VERSION 5.8 ;
BUSBITCHARS "[]" ;
DIVIDERCHAR "/" ;

UNITS
  DATABASE MICRONS 2000 ;
END UNITS

MANUFACTURINGGRID 0.005 ;

SITE core7T
  CLASS CORE ;
  SYMMETRY X Y ;
  SIZE 0.140 BY 0.700 ;
END core7T

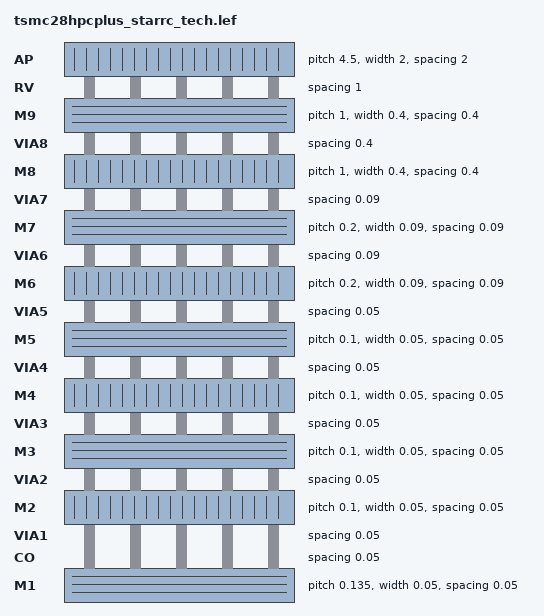
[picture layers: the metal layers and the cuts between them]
LAYER M1
  TYPE ROUTING ;
  DIRECTION HORIZONTAL ;
  PITCH 0.135 ;
  WIDTH 0.050 ;
  SPACING 0.050 ;
END M1

LAYER CO
  TYPE CUT ;
  SPACING 0.050 ;
END CO

LAYER VIA1
  TYPE CUT ;
  SPACING 0.050 ;
END VIA1

LAYER M2
  TYPE ROUTING ;
  DIRECTION VERTICAL ;
  PITCH 0.100 ;
  WIDTH 0.050 ;
  SPACING 0.050 ;
END M2

LAYER VIA2
  TYPE CUT ;
  SPACING 0.050 ;
END VIA2

LAYER M3
  TYPE ROUTING ;
  DIRECTION HORIZONTAL ;
  PITCH 0.100 ;
  WIDTH 0.050 ;
  SPACING 0.050 ;
END M3

LAYER VIA3
  TYPE CUT ;
  SPACING 0.050 ;
END VIA3

LAYER M4
  TYPE ROUTING ;
  DIRECTION VERTICAL ;
  PITCH 0.100 ;
  WIDTH 0.050 ;
  SPACING 0.050 ;
END M4

LAYER VIA4
  TYPE CUT ;
  SPACING 0.050 ;
END VIA4

LAYER M5
  TYPE ROUTING ;
  DIRECTION HORIZONTAL ;
  PITCH 0.100 ;
  WIDTH 0.050 ;
  SPACING 0.050 ;
END M5

LAYER VIA5
  TYPE CUT ;
  SPACING 0.050 ;
END VIA5

LAYER M6
  TYPE ROUTING ;
  DIRECTION VERTICAL ;
  PITCH 0.200 ;
  WIDTH 0.090 ;
  SPACING 0.090 ;
END M6

LAYER VIA6
  TYPE CUT ;
  SPACING 0.090 ;
END VIA6

LAYER M7
  TYPE ROUTING ;
  DIRECTION HORIZONTAL ;
  PITCH 0.200 ;
  WIDTH 0.090 ;
  SPACING 0.090 ;
END M7

LAYER VIA7
  TYPE CUT ;
  SPACING 0.090 ;
END VIA7

LAYER M8
  TYPE ROUTING ;
  DIRECTION VERTICAL ;
  PITCH 1.000 ;
  WIDTH 0.400 ;
  SPACING 0.400 ;
END M8

LAYER VIA8
  TYPE CUT ;
  SPACING 0.400 ;
END VIA8

LAYER M9
  TYPE ROUTING ;
  DIRECTION HORIZONTAL ;
  PITCH 1.000 ;
  WIDTH 0.400 ;
  SPACING 0.400 ;
END M9

LAYER RV
  TYPE CUT ;
  SPACING 1.000 ;
END RV

LAYER AP
  TYPE ROUTING ;
  DIRECTION VERTICAL ;
  PITCH 4.500 ;
  WIDTH 2.000 ;
  SPACING 2.000 ;
END AP

VIA VIA12_1cut DEFAULT
  LAYER M1 ;
    RECT -0.025 -0.055 0.025 0.055 ;
  LAYER VIA1 ;
    RECT -0.025 -0.025 0.025 0.025 ;
  LAYER M2 ;
    RECT -0.055 -0.025 0.055 0.025 ;
END VIA12_1cut

VIA VIA12_square
  LAYER M1 ;
    RECT -0.025 -0.055 0.025 0.055 ;
  LAYER VIA1 ;
    RECT -0.025 -0.025 0.025 0.025 ;
  LAYER M2 ;
    RECT -0.055 -0.025 0.055 0.025 ;
END VIA12_square

VIA VIA12_slot
  LAYER M1 ;
    RECT -0.075 -0.055 0.075 0.055 ;
  LAYER VIA1 ;
    RECT -0.065 -0.025 0.065 0.025 ;
  LAYER M2 ;
    RECT -0.105 -0.025 0.105 0.025 ;
END VIA12_slot

VIA VIA12_1cut_V
  LAYER M1 ;
    RECT -0.025 -0.055 0.025 0.055 ;
  LAYER VIA1 ;
    RECT -0.025 -0.025 0.025 0.025 ;
  LAYER M2 ;
    RECT -0.025 -0.055 0.025 0.055 ;
END VIA12_1cut_V

VIA VIA12_1cut_AS
  LAYER M1 ;
    RECT -0.045 -0.045 0.045 0.045 ;
  LAYER VIA1 ;
    RECT -0.025 -0.025 0.025 0.025 ;
  LAYER M2 ;
    RECT -0.045 -0.045 0.045 0.045 ;
END VIA12_1cut_AS

VIA VIA12_1cut_EN1415
  LAYER M1 ;
    RECT -0.035 -0.05 0.035 0.05 ;
  LAYER VIA1 ;
    RECT -0.025 -0.025 0.025 0.025 ;
  LAYER M2 ;
    RECT -0.05 -0.035 0.05 0.035 ;
END VIA12_1cut_EN1415

VIA VIA12_LONG_H
  LAYER M1 ;
    RECT -0.075 -0.055 0.075 0.055 ;
  LAYER VIA1 ;
    RECT -0.065 -0.025 0.065 0.025 ;
  LAYER M2 ;
    RECT -0.105 -0.025 0.105 0.025 ;
END VIA12_LONG_H

VIA VIA12_LONG_HH
  LAYER M1 ;
    RECT -0.105 -0.025 0.105 0.025 ;
  LAYER VIA1 ;
    RECT -0.065 -0.025 0.065 0.025 ;
  LAYER M2 ;
    RECT -0.105 -0.025 0.105 0.025 ;
END VIA12_LONG_HH

VIA VIA12_LONG_V
  LAYER M1 ;
    RECT -0.025 -0.105 0.025 0.105 ;
  LAYER VIA1 ;
    RECT -0.025 -0.065 0.025 0.065 ;
  LAYER M2 ;
    RECT -0.055 -0.075 0.055 0.075 ;
END VIA12_LONG_V

VIA VIA23_1cut DEFAULT
  LAYER M2 ;
    RECT -0.055 -0.025 0.055 0.025 ;
  LAYER VIA2 ;
    RECT -0.025 -0.025 0.025 0.025 ;
  LAYER M3 ;
    RECT -0.025 -0.055 0.025 0.055 ;
END VIA23_1cut

VIA VIA23_1cut_V
  LAYER M2 ;
    RECT -0.025 -0.055 0.025 0.055 ;
  LAYER VIA2 ;
    RECT -0.025 -0.025 0.025 0.025 ;
  LAYER M3 ;
    RECT -0.025 -0.055 0.025 0.055 ;
END VIA23_1cut_V

VIA VIA23_1cut_AS
  LAYER M2 ;
    RECT -0.045 -0.045 0.045 0.045 ;
  LAYER VIA2 ;
    RECT -0.025 -0.025 0.025 0.025 ;
  LAYER M3 ;
    RECT -0.045 -0.045 0.045 0.045 ;
END VIA23_1cut_AS

VIA VIA23_1cut_EN1415
  LAYER M2 ;
    RECT -0.05 -0.035 0.05 0.035 ;
  LAYER VIA2 ;
    RECT -0.025 -0.025 0.025 0.025 ;
  LAYER M3 ;
    RECT -0.035 -0.05 0.035 0.05 ;
END VIA23_1cut_EN1415

VIA VIA23_LONG_H
  LAYER M2 ;
    RECT -0.105 -0.025 0.105 0.025 ;
  LAYER VIA2 ;
    RECT -0.065 -0.025 0.065 0.025 ;
  LAYER M3 ;
    RECT -0.075 -0.055 0.075 0.055 ;
END VIA23_LONG_H

VIA VIA23_LONG_HH
  LAYER M2 ;
    RECT -0.105 -0.025 0.105 0.025 ;
  LAYER VIA2 ;
    RECT -0.065 -0.025 0.065 0.025 ;
  LAYER M3 ;
    RECT -0.105 -0.025 0.105 0.025 ;
END VIA23_LONG_HH

VIA VIA23_LONG_V
  LAYER M2 ;
    RECT -0.055 -0.075 0.055 0.075 ;
  LAYER VIA2 ;
    RECT -0.025 -0.065 0.025 0.065 ;
  LAYER M3 ;
    RECT -0.025 -0.105 0.025 0.105 ;
END VIA23_LONG_V

VIA VIA23_PBD
  LAYER M2 ;
    RECT -0.105 -0.025 0.105 0.025 ;
  LAYER VIA2 ;
    RECT -0.065 -0.025 0.065 0.025 ;
  LAYER M3 ;
    RECT -0.095 -0.055 0.095 0.055 ;
END VIA23_PBD

VIA VIA23_PBS
  LAYER M2 ;
    RECT -0.055 -0.025 0.055 0.025 ;
  LAYER VIA2 ;
    RECT -0.025 -0.025 0.025 0.025 ;
  LAYER M3 ;
    RECT -0.055 -0.055 0.055 0.055 ;
END VIA23_PBS

VIA VIA23_PBDB
  LAYER M2 ;
    RECT -0.085 -0.045 0.085 0.045 ;
  LAYER VIA2 ;
    RECT -0.065 -0.025 0.065 0.025 ;
  LAYER M3 ;
    RECT -0.105 -0.025 0.105 0.025 ;
END VIA23_PBDB

VIA VIA23_PBDU
  LAYER M2 ;
    RECT -0.105 -0.025 0.105 0.025 ;
  LAYER VIA2 ;
    RECT -0.065 -0.025 0.065 0.025 ;
  LAYER M3 ;
    RECT -0.085 -0.045 0.085 0.045 ;
END VIA23_PBDU

VIA VIA23_PBDE
  LAYER M2 ;
    RECT -0.105 -0.025 0.105 0.025 ;
  LAYER VIA2 ;
    RECT -0.065 -0.025 0.065 0.025 ;
  LAYER M3 ;
    RECT -0.105 -0.025 0.105 0.025 ;
END VIA23_PBDE

VIA VIA23_PBSB
  LAYER M2 ;
    RECT -0.05 -0.035 0.05 0.035 ;
  LAYER VIA2 ;
    RECT -0.025 -0.025 0.025 0.025 ;
  LAYER M3 ;
    RECT -0.025 -0.055 0.025 0.055 ;
END VIA23_PBSB

VIA VIA23_PBSU
  LAYER M2 ;
    RECT -0.055 -0.025 0.055 0.025 ;
  LAYER VIA2 ;
    RECT -0.025 -0.025 0.025 0.025 ;
  LAYER M3 ;
    RECT -0.035 -0.05 0.035 0.05 ;
END VIA23_PBSU

VIA VIA34_1cut DEFAULT
  LAYER M3 ;
    RECT -0.025 -0.055 0.025 0.055 ;
  LAYER VIA3 ;
    RECT -0.025 -0.025 0.025 0.025 ;
  LAYER M4 ;
    RECT -0.055 -0.025 0.055 0.025 ;
END VIA34_1cut

VIA VIA34_1cut_V
  LAYER M3 ;
    RECT -0.025 -0.055 0.025 0.055 ;
  LAYER VIA3 ;
    RECT -0.025 -0.025 0.025 0.025 ;
  LAYER M4 ;
    RECT -0.025 -0.055 0.025 0.055 ;
END VIA34_1cut_V

VIA VIA34_1cut_AS
  LAYER M3 ;
    RECT -0.045 -0.045 0.045 0.045 ;
  LAYER VIA3 ;
    RECT -0.025 -0.025 0.025 0.025 ;
  LAYER M4 ;
    RECT -0.045 -0.045 0.045 0.045 ;
END VIA34_1cut_AS

VIA VIA34_1cut_EN1415
  LAYER M3 ;
    RECT -0.035 -0.05 0.035 0.05 ;
  LAYER VIA3 ;
    RECT -0.025 -0.025 0.025 0.025 ;
  LAYER M4 ;
    RECT -0.05 -0.035 0.05 0.035 ;
END VIA34_1cut_EN1415

VIA VIA34_LONG_HH
  LAYER M3 ;
    RECT -0.105 -0.025 0.105 0.025 ;
  LAYER VIA3 ;
    RECT -0.065 -0.025 0.065 0.025 ;
  LAYER M4 ;
    RECT -0.105 -0.025 0.105 0.025 ;
END VIA34_LONG_HH

VIA VIA45_1cut DEFAULT
  LAYER M4 ;
    RECT -0.055 -0.025 0.055 0.025 ;
  LAYER VIA4 ;
    RECT -0.025 -0.025 0.025 0.025 ;
  LAYER M5 ;
    RECT -0.025 -0.055 0.025 0.055 ;
END VIA45_1cut

VIA VIA45_1cut_V
  LAYER M4 ;
    RECT -0.025 -0.055 0.025 0.055 ;
  LAYER VIA4 ;
    RECT -0.025 -0.025 0.025 0.025 ;
  LAYER M5 ;
    RECT -0.025 -0.055 0.025 0.055 ;
END VIA45_1cut_V

VIA VIA45_1cut_AS
  LAYER M4 ;
    RECT -0.045 -0.045 0.045 0.045 ;
  LAYER VIA4 ;
    RECT -0.025 -0.025 0.025 0.025 ;
  LAYER M5 ;
    RECT -0.045 -0.045 0.045 0.045 ;
END VIA45_1cut_AS

VIA VIA45_1cut_EN1415
  LAYER M4 ;
    RECT -0.05 -0.035 0.05 0.035 ;
  LAYER VIA4 ;
    RECT -0.025 -0.025 0.025 0.025 ;
  LAYER M5 ;
    RECT -0.035 -0.05 0.035 0.05 ;
END VIA45_1cut_EN1415

VIA VIA56_1cut DEFAULT
  LAYER M5 ;
    RECT -0.065 -0.09 0.065 0.09 ;
  LAYER VIA5 ;
    RECT -0.05 -0.05 0.05 0.05 ;
  LAYER M6 ;
    RECT -0.09 -0.05 0.09 0.05 ;
END VIA56_1cut

VIA VIA56_1cut_V
  LAYER M5 ;
    RECT -0.065 -0.09 0.065 0.09 ;
  LAYER VIA5 ;
    RECT -0.05 -0.05 0.05 0.05 ;
  LAYER M6 ;
    RECT -0.05 -0.09 0.05 0.09 ;
END VIA56_1cut_V

VIA VIA67_1cut DEFAULT
  LAYER M6 ;
    RECT -0.09 -0.05 0.09 0.05 ;
  LAYER VIA6 ;
    RECT -0.05 -0.05 0.05 0.05 ;
  LAYER M7 ;
    RECT -0.05 -0.09 0.05 0.09 ;
END VIA67_1cut

VIA VIA23_FBD30
  LAYER M2 ;
    RECT -0.075 -0.055 0.075 0.055 ;
  LAYER VIA2 ;
    RECT -0.065 -0.025 0.065 0.025 ;
  LAYER M3 ;
    RECT -0.075 -0.055 0.075 0.055 ;
END VIA23_FBD30

VIA VIA23_FBD20
  LAYER M2 ;
    RECT -0.085 -0.045 0.085 0.045 ;
  LAYER VIA2 ;
    RECT -0.065 -0.025 0.065 0.025 ;
  LAYER M3 ;
    RECT -0.085 -0.045 0.085 0.045 ;
END VIA23_FBD20

VIA VIA12_PBDB
  LAYER M1 ;
    RECT -0.085 -0.045 0.085 0.045 ;
  LAYER VIA1 ;
    RECT -0.065 -0.025 0.065 0.025 ;
  LAYER M2 ;
    RECT -0.105 -0.025 0.105 0.025 ;
END VIA12_PBDB

VIA VIA12_PBDU
  LAYER M1 ;
    RECT -0.105 -0.025 0.105 0.025 ;
  LAYER VIA1 ;
    RECT -0.065 -0.025 0.065 0.025 ;
  LAYER M2 ;
    RECT -0.085 -0.045 0.085 0.045 ;
END VIA12_PBDU

VIA PGVIA12_RECT
  LAYER M1 ;
    RECT -0.075 -0.055 0.075 0.055 ;
  LAYER VIA1 ;
    RECT -0.065 -0.025 0.065 0.025 ;
  LAYER M2 ;
    RECT -0.105 -0.025 0.105 0.025 ;
END PGVIA12_RECT

VIA VIA12_FBS25
  LAYER M1 ;
    RECT -0.05 -0.05 0.05 0.05 ;
  LAYER VIA1 ;
    RECT -0.025 -0.025 0.025 0.025 ;
  LAYER M2 ;
    RECT -0.05 -0.05 0.05 0.05 ;
END VIA12_FBS25

VIA VIA12_FBD20
  LAYER M1 ;
    RECT -0.085 -0.045 0.085 0.045 ;
  LAYER VIA1 ;
    RECT -0.065 -0.025 0.065 0.025 ;
  LAYER M2 ;
    RECT -0.085 -0.045 0.085 0.045 ;
END VIA12_FBD20

VIA VIA34_LONG_H
  LAYER M3 ;
    RECT -0.075 -0.055 0.075 0.055 ;
  LAYER VIA3 ;
    RECT -0.065 -0.025 0.065 0.025 ;
  LAYER M4 ;
    RECT -0.105 -0.025 0.105 0.025 ;
END VIA34_LONG_H

VIA VIA34_LONG_V
  LAYER M3 ;
    RECT -0.025 -0.105 0.025 0.105 ;
  LAYER VIA3 ;
    RECT -0.025 -0.065 0.025 0.065 ;
  LAYER M4 ;
    RECT -0.055 -0.075 0.055 0.075 ;
END VIA34_LONG_V

VIA VIA45_LONG_V
  LAYER M4 ;
    RECT -0.055 -0.075 0.055 0.075 ;
  LAYER VIA4 ;
    RECT -0.025 -0.065 0.025 0.065 ;
  LAYER M5 ;
    RECT -0.025 -0.105 0.025 0.105 ;
END VIA45_LONG_V

VIA VIA45_LONG_HH
  LAYER M4 ;
    RECT -0.105 -0.025 0.105 0.025 ;
  LAYER VIA4 ;
    RECT -0.065 -0.025 0.065 0.025 ;
  LAYER M5 ;
    RECT -0.105 -0.025 0.105 0.025 ;
END VIA45_LONG_HH

VIA VIA45_FBD20
  LAYER M4 ;
    RECT -0.085 -0.045 0.085 0.045 ;
  LAYER VIA4 ;
    RECT -0.065 -0.025 0.065 0.025 ;
  LAYER M5 ;
    RECT -0.085 -0.045 0.085 0.045 ;
END VIA45_FBD20

END LIBRARY
